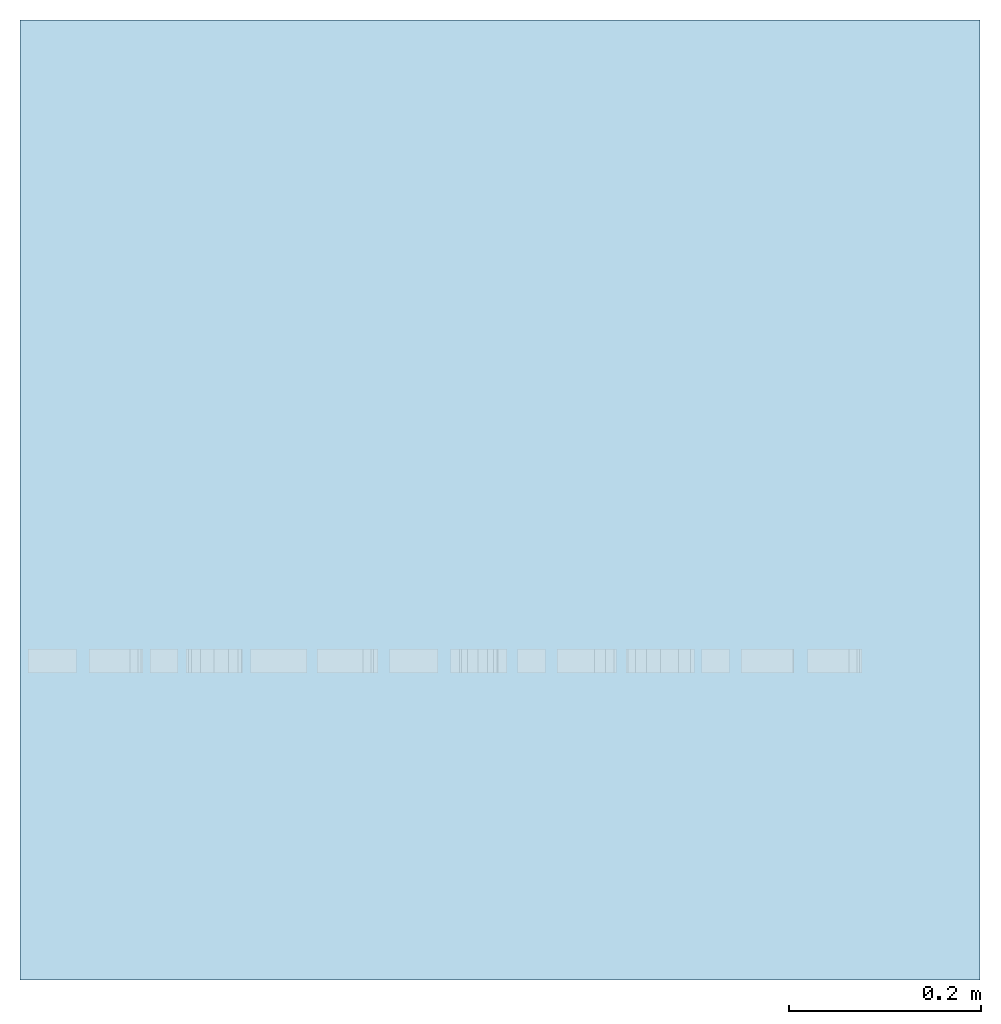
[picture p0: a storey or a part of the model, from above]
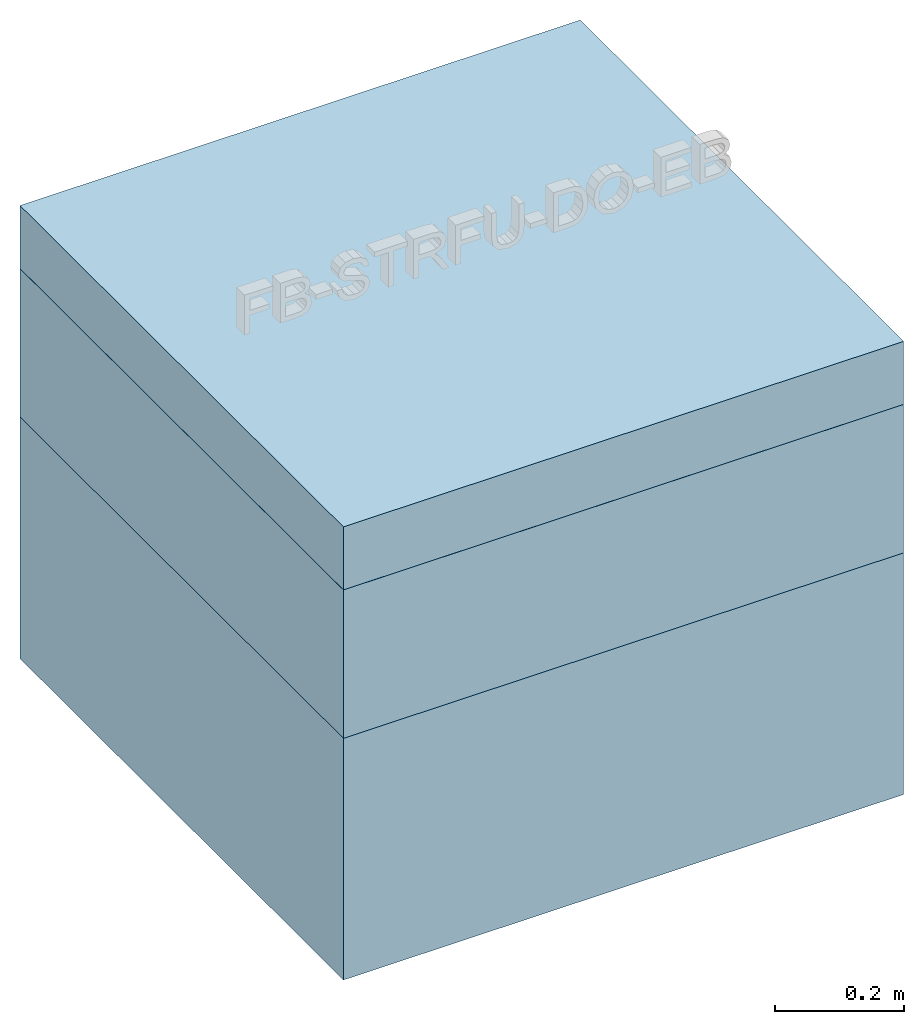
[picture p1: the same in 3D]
Properties of the parts of a building model (IFC4)

# File
Description: ViewDefinition [ReferenceView_V1.2], RevitIdentifiers [VersionGUID: 25224f80-5d8e-4640-b9d8-b88f8e84a847, NumberOfSaves: 3], CoordinateReference [CoordinateBase: Gemeinsam genutzte Koordinaten], ExchangeRequirement [Architecture]
File name: 2018_01
Time: 2023-07-05T11:53:42+01:00
Written by: ODA SDAI 23.12
Made in: Autodesk Revit 24.0.5.432 (DEU) - IFC 24.0.5.432

# IfcProject, 2018_01
Phase: Projekt Status

# IfcSite, Default
RefLatitude: 48, 8, 15, 359802; RefLongitude: 11, 34, 47, 783432; RefElevation: 0 m
Pset_SiteCommon - Reference: Projektinformationen

# IfcBuildingElementProxy: Modelltext:075mm Arial, Modelltext:075mm Arial:2510609
In: Default
Type - Pset_BuildingElementProxyCommon - IsExternal: no
Pset_BuildingElementProxyCommon - Reference: 075mm Arial
Pset_EnvironmentalImpactIndicators - Reference: 075mm Arial
Qto_BuildingElementProxyQuantities - NetSurfaceArea: 0.156214 m2; NetVolume: 0.0005186 m3

# IfcElementAssembly: Geschossdecken Baugruppe:fbimSg_Footing_bc_WOD_vis_at_NTR_natuREbuilt_FB-STRFU-DO-EB_GK3_86cm, Geschossdecken Baugruppe:fbimSg_Footing_bc_WOD_vis_at_NTR_natuREbuilt_FB-STRFU-DO-EB_GK3_86cm:2510631
In: Default
PredefinedType: USERDEFINED; Material: fbim_18108010_AT_015_Parkettboden, fbim_AT_Perlitdaemmschuettung, fbim_14104055_AT_040_HF-Trittschalldaemmplatte, fbim_12400515_AT_025_Vollholz_Bretter_Fichte
Pset_ElementAssemblyCommon - Reference: fbimSg_Footing_bc_WOD_vis_at_NTR_natuREbuilt_FB-STRFU-DO-EB_GK3_86cm; sets with these values: 2

# IfcSlab: Geschossdecke:fbimSg_Floor_dp_INS_vis_at_NTR_natuREbuilt_FBo_GK3_u_12cm, Geschossdecke:fbimSg_Floor_dp_INS_vis_at_NTR_natuREbuilt_FBo_GK3_u_12cm:2510626
In: Default
Type - PredefinedType: FLOOR; Material: fbim_14052005_AT_EPDM_Abdichtungsbahn, fbim_12050505_AT_025_Stahlbeton_C25_30_GK32, fbim_10051510_AT_020_Frostkoffer
Type - Pset_SlabCommon - IsExternal: no
Pset_EnvironmentalImpactIndicators - Reference: fbimSg_Floor_dp_INS_vis_at_NTR_natuREbuilt_FBo_GK3_u_12cm; sets with these values: 2
Pset_SlabCommon - PitchAngle: 0 deg; LoadBearing: no; Reference: fbimSg_Floor_dp_INS_vis_at_NTR_natuREbuilt_FBo_GK3_u_12cm
Qto_SlabBaseQuantities - fbim_14052005_AT_EPDM_Abdichtungsbahn, Width: 0.006 m; fbim_12050505_AT_025_Stahlbeton_C25_30_GK32, Width: 0.15 m; fbim_10051510_AT_020_Frostkoffer, Width: 0.3 m; Width: 0.456 m; Length: 1 m; Depth: 0.3 m; Perimeter: 4 m; GrossArea: 1 m2; GrossVolume: 0.3 m3; NetVolume: 0.456 m3

# IfcSlab: Geschossdecke:fbimSg_Slab_sb_CNR_vis_at_NTR_natuREbuilt_FBo_GK3_o_15cm, Geschossdecke:fbimSg_Slab_sb_CNR_vis_at_NTR_natuREbuilt_FBo_GK3_o_15cm:2510612
In: Default
Type - PredefinedType: FLOOR; Material: fbim_18108010_AT_015_Parkettboden, fbim_AT_Perlitdaemmschuettung, fbim_14104055_AT_040_HF-Trittschalldaemmplatte, fbim_12400515_AT_025_Vollholz_Bretter_Fichte
Type - Pset_SlabCommon - IsExternal: no
Pset_EnvironmentalImpactIndicators - Reference: fbimSg_Slab_sb_CNR_vis_at_NTR_natuREbuilt_FBo_GK3_o_15cm; sets with these values: 2
Pset_SlabCommon - Reference: fbimSg_Slab_sb_CNR_vis_at_NTR_natuREbuilt_FBo_GK3_o_15cm; PitchAngle: 0 deg; LoadBearing: no
Qto_SlabBaseQuantities - fbim_18108010_AT_015_Parkettboden, Width: 0.015 m; fbim_AT_Perlitdaemmschuettung, Width: 0.06 m; fbim_14104055_AT_040_HF-Trittschalldaemmplatte, Width: 0.02 m; fbim_12400515_AT_025_Vollholz_Bretter_Fichte, Width: 0.024 m; Width: 0.119 m; Length: 1 m; Depth: 0.024 m; Perimeter: 4 m; GrossArea: 1 m2; GrossVolume: 0.024 m3; NetVolume: 0.119 m3

# IfcSlab: Geschossdecke:fbimSg_Slab_sb_INS_vis_at_NTR_natuREbuilt_FBo_GK3_k_28cm, Geschossdecke:fbimSg_Slab_sb_INS_vis_at_NTR_natuREbuilt_FBo_GK3_k_28cm:2510619
In: Default
Type - PredefinedType: FLOOR; Material: fbim_14100500_at_NTR_Zellulose-Einblasdaemmung
Type - Pset_SlabCommon - IsExternal: no
Pset_EnvironmentalImpactIndicators - Reference: fbimSg_Slab_sb_INS_vis_at_NTR_natuREbuilt_FBo_GK3_k_28cm; sets with these values: 2
Pset_SlabCommon - PitchAngle: 0 deg; LoadBearing: no; Reference: fbimSg_Slab_sb_INS_vis_at_NTR_natuREbuilt_FBo_GK3_k_28cm
Qto_SlabBaseQuantities - Width: 1 m; Length: 1 m; Depth: 0.28 m; Perimeter: 4 m; GrossArea: 1 m2; GrossVolume: 0.28 m3; NetVolume: 0.28 m3
